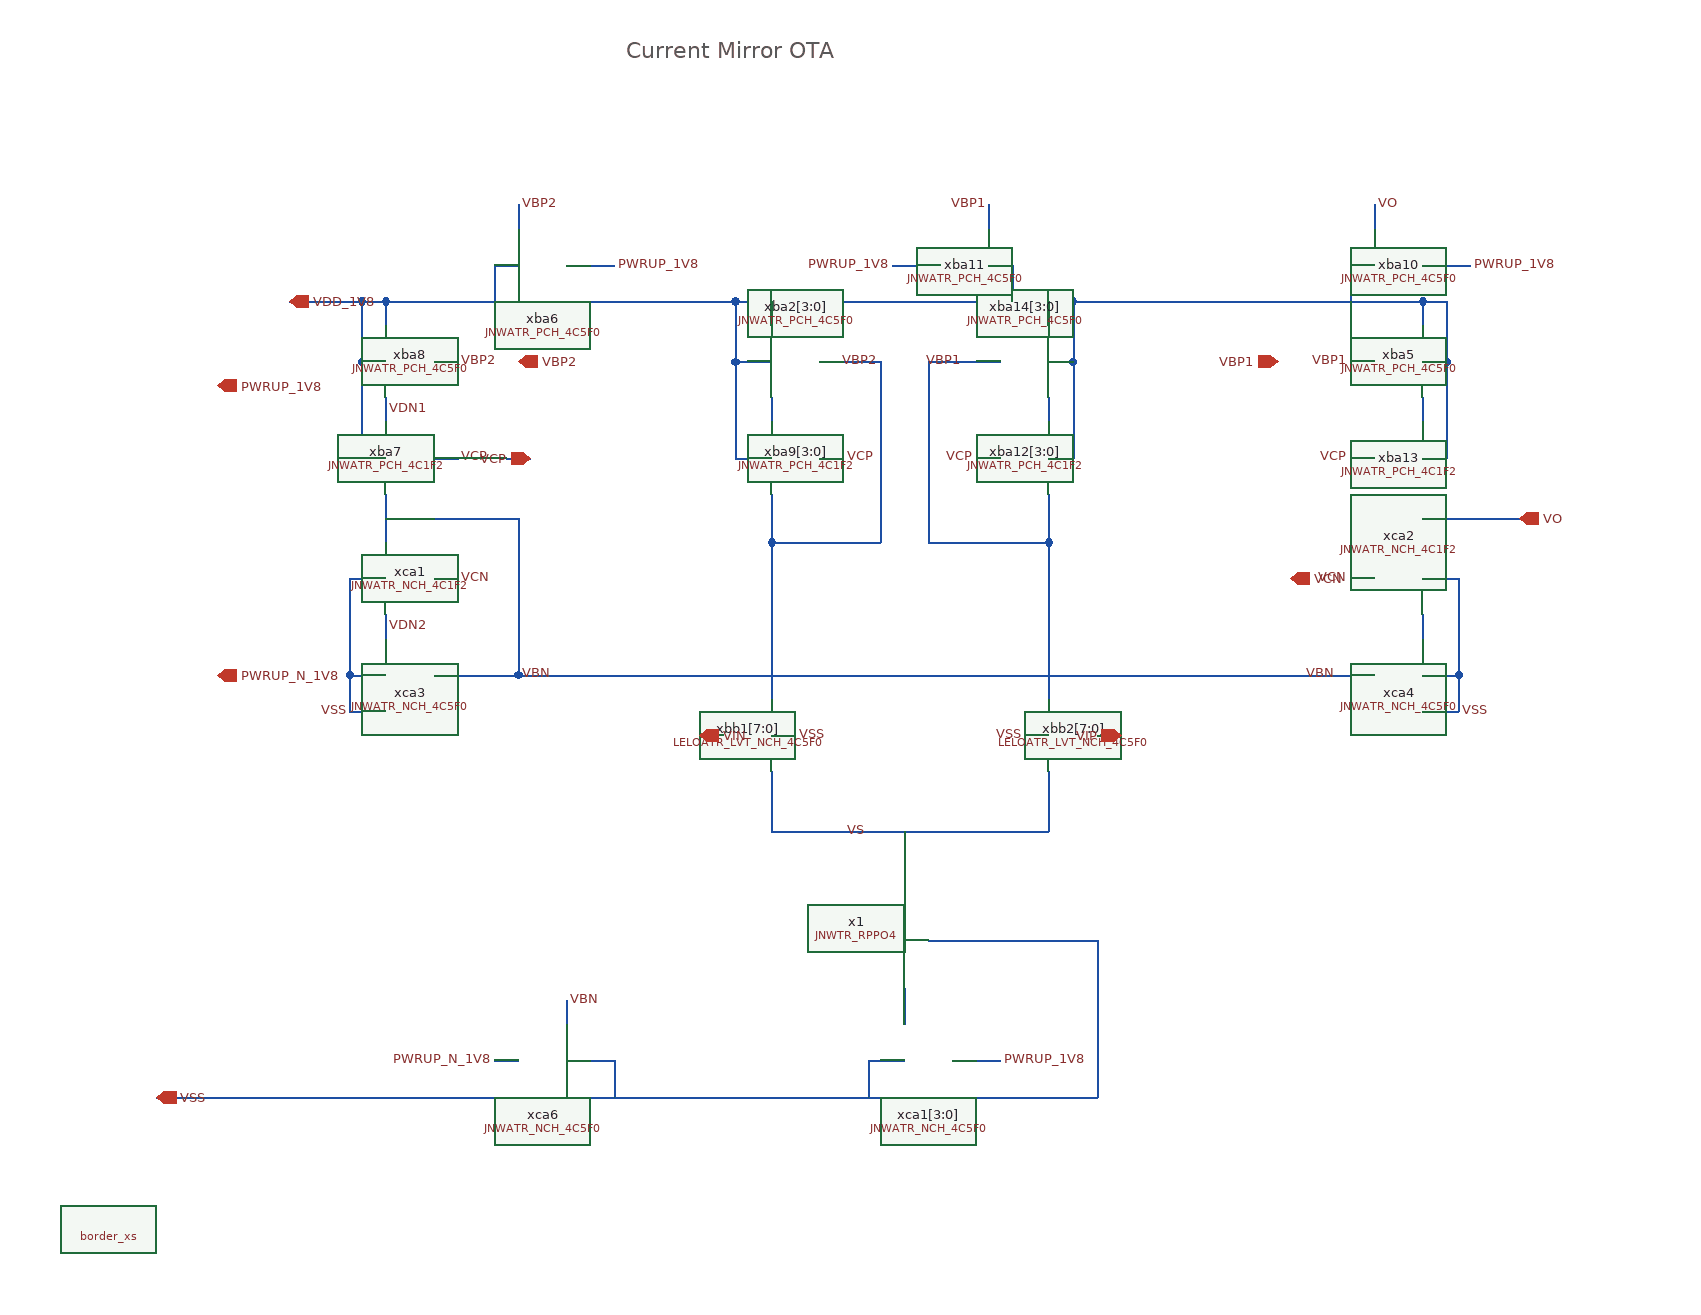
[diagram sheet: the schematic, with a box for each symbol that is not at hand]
v {xschem version=3.4.7 file_version=1.2}
G {}
K {}
V {}
S {}
E {}
T {Current Mirror OTA} 450 -1000 0 0 1 1 {}
N 60 -120 170 -120 {lab=VSS}
N 170 -780 230 -780 {lab=VDD_1V8}
N 570 -390 570 -340 {lab=VS}
N 570 -340 800 -340 {lab=VS}
N 800 -390 800 -340 {lab=VS}
N 680 -340 680 -300 {lab=VS}
N 170 -120 680 -120 {lab=VSS}
N 570 -420 590 -420 {lab=VSS}
N 780 -420 800 -420 {lab=VSS}
N 540 -730 570 -730 {lab=VDD_1V8}
N 540 -780 540 -730 {lab=VDD_1V8}
N 540 -780 820 -780 {lab=VDD_1V8}
N 820 -780 820 -730 {lab=VDD_1V8}
N 800 -730 820 -730 {lab=VDD_1V8}
N 800 -780 800 -760 {lab=VDD_1V8}
N 570 -780 570 -760 {lab=VDD_1V8}
N 820 -730 820 -650 {lab=VDD_1V8}
N 800 -700 800 -680 {lab=#net1}
N 610 -730 660 -730 {lab=VBP2}
N 660 -730 660 -580 {lab=VBP2}
N 570 -580 660 -580 {lab=VBP2}
N 570 -610 570 -580 {lab=VBP2}
N 570 -580 570 -450 {lab=VBP2}
N 700 -730 760 -730 {lab=VBP1}
N 700 -730 700 -580 {lab=VBP1}
N 700 -580 800 -580 {lab=VBP1}
N 800 -620 800 -580 {lab=VBP1}
N 570 -620 570 -610 {lab=VBP2}
N 540 -730 540 -650 {lab=VDD_1V8}
N 800 -580 800 -450 {lab=VBP1}
N 1130 -780 1130 -730 {lab=VDD_1V8}
N 1110 -730 1130 -730 {lab=VDD_1V8}
N 1110 -780 1110 -760 {lab=VDD_1V8}
N 1130 -730 1130 -650 {lab=VDD_1V8}
N 1110 -700 1110 -680 {lab=#net2}
N 1110 -620 1110 -580 {lab=VO}
N 610 -650 630 -650 {lab=VCP}
N 740 -650 760 -650 {lab=VCP}
N 570 -700 570 -680 {lab=#net3}
N 1050 -730 1070 -730 {lab=VBP1}
N 1050 -650 1070 -650 {lab=VCP}
N 820 -780 1110 -780 {lab=VDD_1V8}
N 1110 -780 1130 -780 {lab=VDD_1V8}
N 230 -780 230 -730 {lab=VDD_1V8}
N 230 -730 250 -730 {lab=VDD_1V8}
N 250 -780 250 -760 {lab=VDD_1V8}
N 230 -730 230 -650 {lab=VDD_1V8}
N 250 -700 250 -680 {lab=VDN1}
N 250 -620 250 -580 {lab=VBN}
N 290 -730 310 -730 {lab=VBP2}
N 290 -650 310 -650 {lab=VCP}
N 250 -780 540 -780 {lab=VDD_1V8}
N 230 -780 250 -780 {lab=VDD_1V8}
N 250 -520 250 -500 {lab=VDN2}
N 220 -550 220 -470 {lab=VSS}
N 220 -470 250 -470 {lab=VSS}
N 220 -470 220 -440 {lab=VSS}
N 220 -440 250 -440 {lab=VSS}
N 290 -550 310 -550 {lab=VCN}
N 290 -470 360 -470 {lab=VBN}
N 360 -600 360 -470 {lab=VBN}
N 250 -600 360 -600 {lab=VBN}
N 1110 -620 1110 -580 {lab=VO}
N 1110 -520 1110 -500 {lab=#net4}
N 1140 -550 1140 -470 {lab=VSS}
N 1110 -470 1140 -470 {lab=VSS}
N 1140 -470 1140 -440 {lab=VSS}
N 1110 -440 1140 -440 {lab=VSS}
N 1050 -550 1070 -550 {lab=VCN}
N 1040 -470 1070 -470 {lab=VBN}
N 360 -470 1040 -470 {lab=VBN}
N 1110 -600 1190 -600 {lab=VO}
N 340 -810 360 -810 {lab=VDD_1V8}
N 340 -810 340 -780 {lab=VDD_1V8}
N 360 -860 360 -840 {lab=VBP2}
N 400 -810 440 -810 {lab=PWRUP_1V8}
N 750 -810 770 -810 {lab=VDD_1V8}
N 770 -810 770 -780 {lab=VDD_1V8}
N 750 -860 750 -840 {lab=VBP1}
N 670 -810 710 -810 {lab=PWRUP_1V8}
N 400 -150 440 -150 {lab=VSS}
N 440 -150 440 -120 {lab=VSS}
N 400 -200 400 -180 {lab=VBN}
N 340 -150 360 -150 {lab=PWRUP_N_1V8}
N 840 -420 860 -420 {lab=VIP}
N 510 -420 530 -420 {lab=VIN}
N 1050 -810 1070 -810 {lab=VDD_1V8}
N 1050 -810 1050 -780 {lab=VDD_1V8}
N 1070 -860 1070 -840 {lab=VO}
N 1110 -810 1150 -810 {lab=PWRUP_1V8}
N 680 -120 720 -120 {lab=VSS}
N 650 -150 680 -150 {lab=VSS}
N 650 -150 650 -120 {lab=VSS}
N 720 -150 760 -150 {lab=PWRUP_1V8}
N 230 -650 250 -650 {lab=VDD_1V8}
N 220 -550 250 -550 {lab=VSS}
N 540 -650 570 -650 {lab=VDD_1V8}
N 800 -650 820 -650 {lab=VDD_1V8}
N 1110 -650 1130 -650 {lab=VDD_1V8}
N 680 -300 680 -290 {lab=VS}
N 680 -210 680 -180 {lab=#net5}
N 700 -250 840 -250 {lab=VSS}
N 840 -250 840 -120 {lab=VSS}
N 1110 -550 1140 -550 {lab=VSS}
N 720 -120 840 -120 {lab=VSS}
N 350 -650 370 -650 {lab=VCP}
C {devices/ipin.sym} 170 -780 2 1 {name=p4 lab=VDD_1V8}
C {devices/ipin.sym} 60 -120 2 1 {name=p5 lab=VSS}
C {JNW_ATR_SKY130A/JNWATR_NCH_4C5F0.sym} 290 -470 0 1 {name=xca3}
C {devices/ipin.sym} 110 -470 2 1 {name=p9 lab=PWRUP_N_1V8}
C {devices/ipin.sym} 110 -710 2 1 {name=p10 lab=PWRUP_1V8}
C {cborder/border_xs.sym} 20 -10 0 0 {user="Carsten Wulff" company="Carsten Wulff Software"}
C {LELO_ATR_SKY130A/LELOATR_LVT_NCH_4C5F0.sym} 530 -420 0 0 {name=xbb1[7:0]}
C {LELO_ATR_SKY130A/LELOATR_LVT_NCH_4C5F0.sym} 840 -420 0 1 {name=xbb2[7:0]}
C {devices/lab_wire.sym} 590 -420 0 1 {name=p1 sig_type=std_logic lab=VSS}
C {devices/lab_wire.sym} 780 -420 0 0 {name=p2 sig_type=std_logic lab=VSS}
C {devices/lab_wire.sym} 650 -340 0 0 {name=p7 sig_type=std_logic lab=VS}
C {JNW_ATR_SKY130A/JNWATR_PCH_4C5F0.sym} 610 -730 0 1 {name=xba2[3:0]}
C {JNW_ATR_SKY130A/JNWATR_PCH_4C5F0.sym} 760 -730 0 0 {name=xba14[3:0]}
C {JNW_ATR_SKY130A/JNWATR_PCH_4C5F0.sym} 1070 -730 0 0 {name=xba5}
C {devices/lab_wire.sym} 630 -650 0 1 {name=p8 sig_type=std_logic lab=VCP}
C {devices/lab_wire.sym} 740 -650 0 0 {name=p11 sig_type=std_logic lab=VCP}
C {devices/lab_wire.sym} 730 -730 0 0 {name=p12 sig_type=std_logic lab=VBP1}
C {devices/lab_wire.sym} 660 -730 0 0 {name=p14 sig_type=std_logic lab=VBP2}
C {devices/lab_wire.sym} 1050 -730 0 0 {name=p16 sig_type=std_logic lab=VBP1}
C {devices/lab_wire.sym} 1050 -650 0 0 {name=p17 sig_type=std_logic lab=VCP}
C {JNW_ATR_SKY130A/JNWATR_PCH_4C5F0.sym} 290 -730 0 1 {name=xba8}
C {devices/lab_wire.sym} 310 -730 0 1 {name=p18 sig_type=std_logic lab=VBP2
}
C {devices/lab_wire.sym} 310 -650 0 1 {name=p19 sig_type=std_logic lab=VCP}
C {devices/lab_wire.sym} 310 -550 0 1 {name=p13 sig_type=std_logic lab=VCN}
C {devices/lab_wire.sym} 360 -470 0 1 {name=p20 sig_type=std_logic lab=VBN}
C {devices/lab_wire.sym} 220 -440 0 0 {name=p21 sig_type=std_logic lab=VSS}
C {JNW_ATR_SKY130A/JNWATR_NCH_4C5F0.sym} 1070 -470 0 0 {name=xca4}
C {devices/lab_wire.sym} 1050 -550 0 0 {name=p22 sig_type=std_logic lab=VCN}
C {devices/lab_wire.sym} 1140 -440 0 1 {name=p23 sig_type=std_logic lab=VSS}
C {devices/lab_wire.sym} 1040 -470 0 0 {name=p24 sig_type=std_logic lab=VBN}
C {devices/opin.sym} 1190 -600 0 0 {name=p25 lab=VO}
C {JNW_ATR_SKY130A/JNWATR_PCH_4C5F0.sym} 400 -810 2 0 {name=xba6}
C {devices/lab_wire.sym} 440 -810 0 1 {name=p26 sig_type=std_logic lab=PWRUP_1V8
}
C {devices/lab_wire.sym} 360 -860 0 1 {name=p27 sig_type=std_logic lab=VBP2
}
C {JNW_ATR_SKY130A/JNWATR_PCH_4C5F0.sym} 710 -810 2 1 {name=xba11}
C {devices/lab_wire.sym} 670 -810 0 0 {name=p28 sig_type=std_logic lab=PWRUP_1V8
}
C {devices/lab_wire.sym} 750 -860 0 0 {name=p29 sig_type=std_logic lab=VBP1
}
C {JNW_ATR_SKY130A/JNWATR_NCH_4C5F0.sym} 360 -150 0 0 {name=xca6}
C {devices/lab_wire.sym} 340 -150 0 0 {name=p30 sig_type=std_logic lab=PWRUP_N_1V8}
C {devices/lab_wire.sym} 400 -200 0 1 {name=p31 sig_type=std_logic lab=VBN}
C {devices/ipin.sym} 860 -420 2 0 {name=p33 lab=VIP}
C {devices/ipin.sym} 510 -420 2 1 {name=p34 lab=VIN}
C {JNW_ATR_SKY130A/JNWATR_PCH_4C5F0.sym} 1110 -810 2 0 {name=xba10}
C {devices/lab_wire.sym} 1150 -810 0 1 {name=p50 sig_type=std_logic lab=PWRUP_1V8
}
C {devices/lab_wire.sym} 1070 -860 0 1 {name=p51 sig_type=std_logic lab=VO
}
C {JNW_ATR_SKY130A/JNWATR_NCH_4C5F0.sym} 720 -150 0 1 {name=xca1[3:0]}
C {devices/lab_wire.sym} 760 -150 0 1 {name=p15 sig_type=std_logic lab=PWRUP_1V8}
C {JNW_ATR_SKY130A/JNWATR_PCH_4C1F2.sym} 290 -650 0 1 {name=xba7}
C {JNW_ATR_SKY130A/JNWATR_NCH_4C1F2.sym} 290 -550 0 1 {name=xca1}
C {JNW_ATR_SKY130A/JNWATR_NCH_4C1F2.sym} 1070 -550 0 0 {name=xca2}
C {JNW_ATR_SKY130A/JNWATR_PCH_4C1F2.sym} 610 -650 0 1 {name=xba9[3:0]}
C {JNW_ATR_SKY130A/JNWATR_PCH_4C1F2.sym} 760 -650 0 0 {name=xba12[3:0]}
C {JNW_ATR_SKY130A/JNWATR_PCH_4C1F2.sym} 1070 -650 0 0 {name=xba13}
C {JNW_TR_SKY130A/JNWTR_RPPO4.sym} 680 -210 3 0 {name=x1 }
C {devices/lab_wire.sym} 250 -690 0 1 {name=p62 sig_type=std_logic lab=VDN1
}
C {devices/lab_wire.sym} 250 -510 0 1 {name=p63 sig_type=std_logic lab=VDN2
}
C {devices/ipin.sym} 370 -650 2 0 {name=p3 lab=VCP
}
C {devices/ipin.sym} 1000 -550 2 1 {name=p6 lab=VCN
}
C {devices/opin.sym} 360 -730 0 0 {name=p32 lab=VBP2
}
C {devices/opin.sym} 990 -730 0 1 {name=p35 lab=VBP1
}
